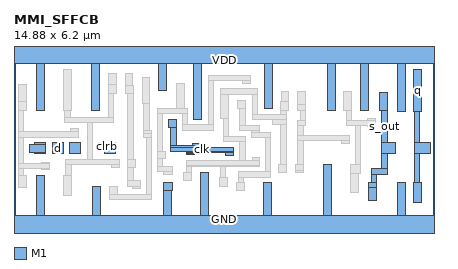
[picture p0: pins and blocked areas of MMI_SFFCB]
MACRO MMI_SFFCB
	CLASS CORE ;
	FOREIGN MMI_SFFCB 0 0 ;
	SIZE 14.88 BY 6.2 ;
	SYMMETRY X Y ;
	SITE CORE1 ;
	PIN d
		DIRECTION input ;
		USE SIGNAL ;
		PORT
			LAYER M1 ;
			RECT 1.36 2.6 1.74 2.98 ;
		END
		AntennaGateArea 0.3465 ;
	END d
	PIN GND
		DIRECTION inout ;
		USE GROUND ;
		PORT
			LAYER M1 ;
			RECT 0.79 0.42 1.07 1.82 ;
			LAYER M1 ;
			RECT 2.795 0.42 3.075 1.435 ;
			LAYER M1 ;
			RECT 5.3 1.28 5.615 1.56 ;
			LAYER M1 ;
			RECT 5.31 0.42 5.59 1.28 ;
			LAYER M1 ;
			RECT 6.6 0.42 6.88 1.945 ;
			LAYER M1 ;
			RECT 8.83 0.42 9.11 1.57 ;
			LAYER M1 ;
			RECT 10.965 0.42 11.245 2.21 ;
			LAYER M1 ;
			RECT 13.58 0.42 13.86 1.58 ;
			LAYER M1 ;
			RECT 0 -0.42 14.885 0.42 ;
		END
	END GND
	PIN q
		DIRECTION output ;
		USE SIGNAL ;
		PORT
			LAYER M1 ;
			RECT 14.17 4.105 14.45 5.575 ;
			LAYER M1 ;
			RECT 14.175 2.98 14.37 4.105 ;
			LAYER M1 ;
			RECT 14.175 2.6 14.76 2.98 ;
			LAYER M1 ;
			RECT 14.175 1.58 14.37 2.6 ;
			LAYER M1 ;
			RECT 14.17 0.88 14.45 1.58 ;
		END
		AntennaDiffArea 0.91245 ;
	END q
	PIN s_en
		DIRECTION input ;
		USE SIGNAL ;
		PORT
			LAYER M1 ;
			RECT 0.74 2.93 1.12 2.98 ;
			LAYER M1 ;
			RECT 0.555 2.65 1.12 2.93 ;
			LAYER M1 ;
			RECT 0.74 2.6 1.12 2.65 ;
		END
		AntennaGateArea 0.72675 ;
	END s_en
	PIN s_in
		DIRECTION input ;
		USE SIGNAL ;
		PORT
			LAYER M1 ;
			RECT 1.98 2.6 2.36 2.98 ;
		END
		AntennaGateArea 0.17325 ;
	END s_in
	PIN VDD
		DIRECTION inout ;
		USE POWER ;
		PORT
			LAYER M1 ;
			RECT 0 5.78 14.885 6.62 ;
			LAYER M1 ;
			RECT 0.79 4.11 1.07 5.78 ;
			LAYER M1 ;
			RECT 2.755 4.115 3.035 5.78 ;
			LAYER M1 ;
			RECT 5.125 4.82 5.405 5.78 ;
			LAYER M1 ;
			RECT 6.36 3.825 6.64 5.78 ;
			LAYER M1 ;
			RECT 8.87 4.2 9.15 5.78 ;
			LAYER M1 ;
			RECT 11.1 4.115 11.38 5.78 ;
			LAYER M1 ;
			RECT 12.28 4.115 12.56 5.78 ;
			LAYER M1 ;
			RECT 13.58 4.105 13.86 5.78 ;
		END
	END VDD
	PIN s_out
		DIRECTION output ;
		USE SIGNAL ;
		PORT
			LAYER M1 ;
			RECT 12.945 4.115 13.225 4.75 ;
			LAYER M1 ;
			RECT 13.025 2.98 13.22 4.115 ;
			LAYER M1 ;
			RECT 13.025 2.6 13.52 2.98 ;
			LAYER M1 ;
			RECT 13.025 2.07 13.22 2.6 ;
			LAYER M1 ;
			RECT 12.665 1.875 13.22 2.07 ;
			LAYER M1 ;
			RECT 12.665 1.585 12.86 1.875 ;
			LAYER M1 ;
			RECT 12.575 1.41 12.86 1.585 ;
			LAYER M1 ;
			RECT 12.575 0.95 12.855 1.41 ;
		END
		AntennaDiffArea 0.59925 ;
	END s_out
	PIN clk
		DIRECTION input ;
		USE CLOCK ;
		PORT
			LAYER M1 ;
			RECT 5.475 3.525 5.755 3.805 ;
			LAYER M1 ;
			RECT 5.56 2.875 5.755 3.525 ;
			LAYER M1 ;
			RECT 6.32 2.875 6.7 2.975 ;
			LAYER M1 ;
			RECT 5.56 2.83 6.7 2.875 ;
			LAYER M1 ;
			RECT 5.56 2.68 7.79 2.83 ;
			LAYER M1 ;
			RECT 6.115 2.635 7.79 2.68 ;
			LAYER M1 ;
			RECT 6.115 2.595 6.7 2.635 ;
			LAYER M1 ;
			RECT 6.115 2.585 6.395 2.595 ;
			LAYER M1 ;
			RECT 7.51 2.55 7.79 2.635 ;
		END
		AntennaGateArea 0.44625 ;
	END clk
	PIN clrb
		DIRECTION input ;
		USE SIGNAL ;
		PORT
			LAYER M1 ;
			RECT 2.99 2.7 3.6 2.98 ;
			LAYER M1 ;
			RECT 3.22 2.6 3.6 2.7 ;
		END
		AntennaGateArea 0.498 ;
	END clrb
	OBS
		LAYER M1 ;
		RECT 0.16 4.455 0.44 5.045 ;
		LAYER M1 ;
		RECT 0.15 4.11 0.44 4.455 ;
		LAYER M1 ;
		RECT 1.75 4.11 2.03 5.58 ;
		LAYER M1 ;
		RECT 3.345 5.035 3.625 5.425 ;
		LAYER M1 ;
		RECT 3.335 4.725 3.625 5.035 ;
		LAYER M1 ;
		RECT 3.935 5.02 4.215 5.425 ;
		LAYER M1 ;
		RECT 3.935 4.725 4.225 5.02 ;
		LAYER M1 ;
		RECT 0.15 3.375 0.345 4.11 ;
		LAYER M1 ;
		RECT 1.8 3.885 1.995 4.11 ;
		LAYER M1 ;
		RECT 3.335 3.885 3.53 4.725 ;
		LAYER M1 ;
		RECT 1.8 3.695 3.53 3.885 ;
		LAYER M1 ;
		RECT 1.99 3.375 2.27 3.495 ;
		LAYER M1 ;
		RECT 0.15 3.18 2.27 3.375 ;
		LAYER M1 ;
		RECT 0.15 2.25 0.345 3.18 ;
		LAYER M1 ;
		RECT 2.59 2.395 2.785 3.695 ;
		LAYER M1 ;
		RECT 4.03 2.4 4.225 4.725 ;
		LAYER M1 ;
		RECT 4.535 4.37 4.815 5.305 ;
		LAYER M1 ;
		RECT 4.6 3.435 4.795 4.37 ;
		LAYER M1 ;
		RECT 5.76 4.195 6.04 5.09 ;
		LAYER M1 ;
		RECT 5.085 4.005 6.16 4.195 ;
		LAYER M1 ;
		RECT 4.6 3.33 4.885 3.435 ;
		LAYER M1 ;
		RECT 4.605 3.155 4.885 3.33 ;
		LAYER M1 ;
		RECT 3.445 2.395 3.725 2.4 ;
		LAYER M1 ;
		RECT 0.985 2.25 1.265 2.3 ;
		LAYER M1 ;
		RECT 0.15 2.055 1.265 2.25 ;
		LAYER M1 ;
		RECT 0.15 1.825 0.345 2.055 ;
		LAYER M1 ;
		RECT 0.985 2.02 1.265 2.055 ;
		LAYER M1 ;
		RECT 1.84 2.2 3.725 2.395 ;
		LAYER M1 ;
		RECT 0.15 1.39 0.44 1.825 ;
		LAYER M1 ;
		RECT 1.84 1.82 2.03 2.2 ;
		LAYER M1 ;
		RECT 3.445 2.12 3.725 2.2 ;
		LAYER M1 ;
		RECT 4.03 2.12 4.315 2.4 ;
		LAYER M1 ;
		RECT 1.75 1.12 2.03 1.82 ;
		LAYER M1 ;
		RECT 4.03 1.635 4.225 2.12 ;
		LAYER M1 ;
		RECT 4.03 1.435 4.49 1.635 ;
		LAYER M1 ;
		RECT 3.385 1.155 3.665 1.435 ;
		LAYER M1 ;
		RECT 4.21 1.355 4.49 1.435 ;
		LAYER M1 ;
		RECT 4.69 1.155 4.88 3.155 ;
		LAYER M1 ;
		RECT 5.085 2.69 5.275 4.005 ;
		LAYER M1 ;
		RECT 5.965 3.625 6.16 4.005 ;
		LAYER M1 ;
		RECT 6.88 5.185 8.385 5.38 ;
		LAYER M1 ;
		RECT 6.88 3.625 7.075 5.185 ;
		LAYER M1 ;
		RECT 8.105 5.1 8.385 5.185 ;
		LAYER M1 ;
		RECT 7.505 4.89 8.635 4.895 ;
		LAYER M1 ;
		RECT 7.32 4.7 8.635 4.89 ;
		LAYER M1 ;
		RECT 7.32 3.83 7.6 4.7 ;
		LAYER M1 ;
		RECT 7.91 4.2 8.19 4.48 ;
		LAYER M1 ;
		RECT 5.965 3.43 7.075 3.625 ;
		LAYER M1 ;
		RECT 7.41 3.22 7.6 3.83 ;
		LAYER M1 ;
		RECT 7.995 3.61 8.185 4.2 ;
		LAYER M1 ;
		RECT 8.445 4 8.635 4.7 ;
		LAYER M1 ;
		RECT 9.46 4.445 9.74 4.815 ;
		LAYER M1 ;
		RECT 9.455 4.115 9.74 4.445 ;
		LAYER M1 ;
		RECT 10.05 4.35 10.33 4.815 ;
		LAYER M1 ;
		RECT 10.05 4.115 10.34 4.35 ;
		LAYER M1 ;
		RECT 11.69 4.115 11.97 4.815 ;
		LAYER M1 ;
		RECT 9.455 4 9.645 4.115 ;
		LAYER M1 ;
		RECT 8.445 3.81 9.645 4 ;
		LAYER M1 ;
		RECT 9.175 3.64 9.645 3.81 ;
		LAYER M1 ;
		RECT 10.15 3.785 10.34 4.115 ;
		LAYER M1 ;
		RECT 7.995 3.42 8.695 3.61 ;
		LAYER M1 ;
		RECT 8.41 3.365 8.695 3.42 ;
		LAYER M1 ;
		RECT 7.41 3.03 8.19 3.22 ;
		LAYER M1 ;
		RECT 8.41 3.175 9.105 3.365 ;
		LAYER M1 ;
		RECT 8.5 3.17 9.105 3.175 ;
		LAYER M1 ;
		RECT 5.08 2.41 5.36 2.69 ;
		LAYER M1 ;
		RECT 5.085 2.15 5.275 2.41 ;
		LAYER M1 ;
		RECT 8 2.35 8.19 3.03 ;
		LAYER M1 ;
		RECT 8.435 2.35 8.715 2.46 ;
		LAYER M1 ;
		RECT 6.095 2.18 8.715 2.35 ;
		LAYER M1 ;
		RECT 6.095 2.16 8.705 2.18 ;
		LAYER M1 ;
		RECT 5.085 1.96 5.615 2.15 ;
		LAYER M1 ;
		RECT 5.3 1.87 5.615 1.96 ;
		LAYER M1 ;
		RECT 6.095 1.945 6.29 2.16 ;
		LAYER M1 ;
		RECT 6.01 1.63 6.29 1.945 ;
		LAYER M1 ;
		RECT 3.385 0.965 4.88 1.155 ;
		LAYER M1 ;
		RECT 7.3 1.765 7.49 2.16 ;
		LAYER M1 ;
		RECT 8.915 1.96 9.105 3.17 ;
		LAYER M1 ;
		RECT 9.455 2.21 9.645 3.64 ;
		LAYER M1 ;
		RECT 10.055 3.59 10.34 3.785 ;
		LAYER M1 ;
		RECT 11.77 3.785 11.965 4.115 ;
		LAYER M1 ;
		RECT 12.535 3.785 12.815 3.835 ;
		LAYER M1 ;
		RECT 11.77 3.59 12.815 3.785 ;
		LAYER M1 ;
		RECT 10.055 3.245 10.25 3.59 ;
		LAYER M1 ;
		RECT 10.055 3.24 11.765 3.245 ;
		LAYER M1 ;
		RECT 10.055 3.05 11.88 3.24 ;
		LAYER M1 ;
		RECT 10.055 2.21 10.25 3.05 ;
		LAYER M1 ;
		RECT 11.6 2.96 11.88 3.05 ;
		LAYER M1 ;
		RECT 12.09 2.21 12.28 3.59 ;
		LAYER M1 ;
		RECT 12.535 3.555 12.815 3.59 ;
		LAYER M1 ;
		RECT 7.955 1.77 9.105 1.96 ;
		LAYER M1 ;
		RECT 9.37 1.93 9.65 2.21 ;
		LAYER M1 ;
		RECT 9.96 2.005 10.25 2.21 ;
		LAYER M1 ;
		RECT 9.96 1.93 10.24 2.005 ;
		LAYER M1 ;
		RECT 7.28 1.45 7.56 1.765 ;
		LAYER M1 ;
		RECT 7.955 1.57 8.145 1.77 ;
		LAYER M1 ;
		RECT 7.87 1.29 8.15 1.57 ;
		LAYER M1 ;
		RECT 11.935 1.895 12.28 2.21 ;
		LAYER M1 ;
		RECT 11.935 1.24 12.215 1.895 ;
	END
END MMI_SFFCB
